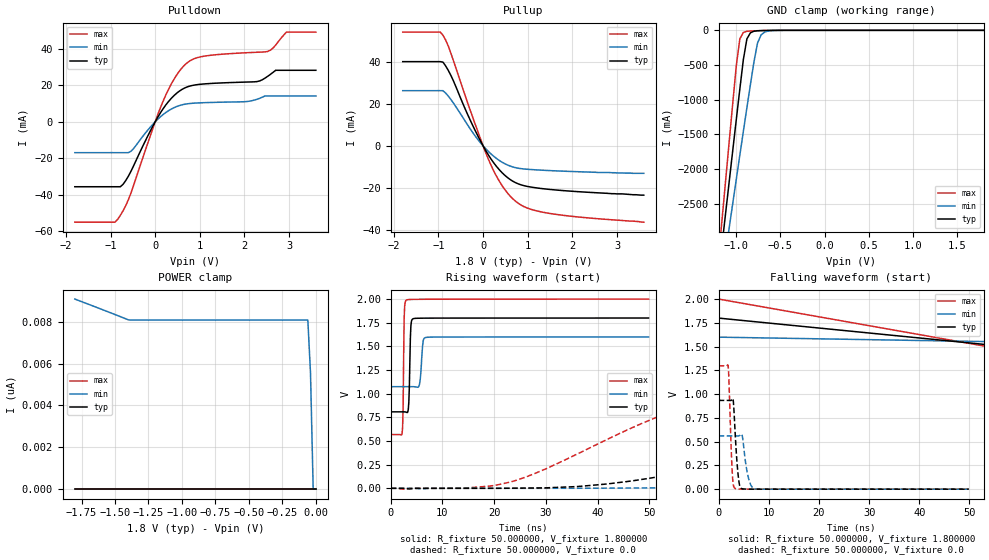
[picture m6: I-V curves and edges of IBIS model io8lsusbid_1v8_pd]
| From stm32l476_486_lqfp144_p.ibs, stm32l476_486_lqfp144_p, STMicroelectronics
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|   Model io8lsusbid_1v8_pd
[Model]  io8lsusbid_1v8_pd
Model_type I/O
Polarity   Non-Inverting
Enable   Active-Low
Vinl =   0.540000V
Vinh =   1.260000V
Vmeas =  0.900000V
Cref =   100.000000nF
Rref =   1.000000k
Vref =   1.800000V
C_comp   2.022300pF   2.021100pF   2.049600pF
[Temperature Range]   25.000000   0.125000k   -40.000000
[Pullup Reference]   1.800000V   1.600000V   2.000000V
[Pulldown Reference]   0.0V   0.0V   0.0V
[POWER Clamp Reference]   1.800000V   1.600000V   2.000000V
[GND Clamp Reference]   0.0V   0.0V   0.0V
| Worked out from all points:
|   slope of the pulldown table from 0 to 0.27 V, typ, clamps not added: 26.4 ohm
|   slope of the pullup table from 0 to 0.27 V, typ, clamps not added: 30.1 ohm
|   GND clamp passes 1 mA (typ) near -0.60 V on its own axis
|   rising waveform, R_fixture 50.000000, V_fixture 1.800000: 20-80 % time 250ps typ, 397ps min, 180ps max; typ from 0.808 V to 1.8 V
|   rising waveform, R_fixture 50.000000, V_fixture 0.0: 20-80 % time 65.2ns typ, 114ns min, 35.5ns max; typ from 0 V to 0.933 V
|   falling waveform, R_fixture 50.000000, V_fixture 1.800000: 20-80 % time 119ns typ, 161ns min, 92ns max; typ from 1.8 V to 0.808 V
|   falling waveform, R_fixture 50.000000, V_fixture 0.0: 20-80 % time 677ps typ, 985ps min, 516ps max; typ from 0.933 V to 0 V
[Pulldown]
|Voltage   I(typ)   I(min)   I(max)
-1.8V     -35.64mA   -16.93mA   -55.1mA
-840mV    -35.64mA   -16.93mA   -53.52mA
-720mV    -34.31mA   -16.93mA   -48.86mA
-540mV    -27.04mA   -16.13mA   -38.89mA
240mV     9.303mA    5.14mA     14.78mA
480mV     15.67mA    8.374mA    25.64mA
720mV     19.18mA    9.883mA    32.46mA
1.14V     20.87mA    10.54mA    36.19mA
2.28V     22.08mA    12.36mA    38.18mA
2.52V     24.96mA    14.18mA    38.63mA
2.94V     28.28mA    14.18mA    49.25mA
3.6V      28.28mA    14.18mA    49.25mA
[Pullup]
|Voltage   I(typ)   I(min)   I(max)
-1.8V     40.17mA    26.34mA    54.27mA
-960mV    40.17mA    26.34mA    54.27mA
-900mV    39.95mA    26.34mA    52.79mA
-780mV    36.01mA    23.74mA    47.65mA
-240mV    10.08mA    6.588mA    14.1mA
120mV     -4.38mA    -2.702mA   -6.45mA
240mV     -8.143mA   -5.004mA   -12mA
420mV     -12.68mA   -7.723mA   -18.77mA
720mV     -17.48mA   -10.37mA   -26.28mA
1.02V     -19.45mA   -11.2mA    -29.89mA
1.5V      -20.78mA   -11.79mA   -32.25mA
3.6V      -23.5mA    -13.1mA    -36.4mA
[GND_clamp]
|Voltage   I(typ)   I(min)   I(max)
-1.8V     -9.895A    -9.296A    -9.457A
-1.2V     -3.533A    -3.902A    -3.274A
-1.16V    -3.082A    -3.55A     -2.716A
-1.12V    -2.631A    -3.198A    -2.159A
-1.08V    -2.182A    -2.848A    -1.604A
-1V       -1.289A    -2.15A     -512mA
-960mV    -849.4mA   -1.803A    -123.8mA
-920mV    -422.4mA   -1.459A    -30.8mA
-880mV    -123.7mA   -1.118A    -13.64mA
-760mV    -6.331mA   -185.1mA   -5.703mA
-680mV    -2.582mA   -25.44mA   -2.917mA
1.8V      47.51uA    51.77uA    39.14uA
[POWER_clamp]
|Voltage   I(typ)   I(min)   I(max)
-1.8V     0A         9.088nA    0A
-1.4V     0A         8.095nA    0A
-60mV     0A         8.084nA    0A
-40mV     0A         5.54nA     0A
-20mV     0A         0A         0A
0V        0A         0A         0A
[Ramp]
| variable   typ   min   max
dV/dt_r  0.56008/65.14355n   0.33658/0.11418u   0.77826/35.46396n
dV/dt_f  0.59478/66.76513n   0.31500/0.11624u   0.85884/34.98706n
R_load = 50.000000
[Rising Waveform]
R_fixture= 50.000000
V_fixture= 1.800000
V_fixture_min= 1.600000
V_fixture_max= 2.000000
|time   V(typ)   V(min)   V(max)
0s        807.9mV    1.074V     568mV
2.202ns   808mV      1.074V     578.5mV
2.402ns   808mV      1.074V     854.5mV
2.603ns   807.9mV    1.074V     1.796V
3.003ns   804.1mV    1.074V     1.988V
3.504ns   909.1mV    1.074V     1.994V
3.904ns   1.718V     1.074V     1.995V
4.404ns   1.793V     1.074V     1.996V
6.807ns   1.798V     1.594V     1.997V
49.85ns   1.799V     1.599V     1.999V
[Rising Waveform]
R_fixture= 50.000000
V_fixture= 0.0
V_fixture_min= 0.0
V_fixture_max= 0.0
|time   V(typ)   V(min)   V(max)
0s        2.451nV    61.35nV    1.823nV
14.41ns   -57.33uV   -36.45uV   2.605mV
22.82ns   947.5uV    -21.17uV   62.61mV
42.04ns   47.24mV    1.669mV    522.1mV
64.86ns   258mV      15.76mV    999.5mV
81.68ns   438.4mV    43.77mV    1.173V
102.1ns   619.7mV    105.1mV    1.25V
156.2ns   858mV      294.9mV    1.292V
254.7ns   928.1mV    496.2mV    1.297V
598.2ns   933.5mV    560.6mV    1.297V
[Falling Waveform]
R_fixture= 50.000000
V_fixture= 1.800000
V_fixture_min= 1.600000
V_fixture_max= 2.000000
|time   V(typ)   V(min)   V(max)
0s        1.799V     1.599V     1.999V
150.2ns   1.015V     1.467V     597.7mV
300.3ns   820.3mV    1.137V     568.7mV
450.5ns   809.1mV    1.086V     568mV
750.8ns   807.9mV    1.075V     568mV
14.86us   807.9mV    1.074V     568mV
[Falling Waveform]
R_fixture= 50.000000
V_fixture= 0.0
V_fixture_min= 0.0
V_fixture_max= 0.0
|time   V(typ)   V(min)   V(max)
0s        933.5mV    560.6mV    1.297V
1.902ns   933.5mV    560.6mV    1.303V
2.703ns   945mV      560.6mV    191.4mV
2.903ns   941.8mV    560.6mV    53.39mV
3.303ns   585.2mV    560.5mV    7.214mV
4.004ns   97.7mV     560.3mV    1.122mV
4.705ns   4.645mV    564mV      346.3uV
5.806ns   337.8uV    150.6mV    148.9uV
7.107ns   -54.63uV   3.62mV     107.1uV
49.85ns   2.451nV    61.35nV    1.823nV
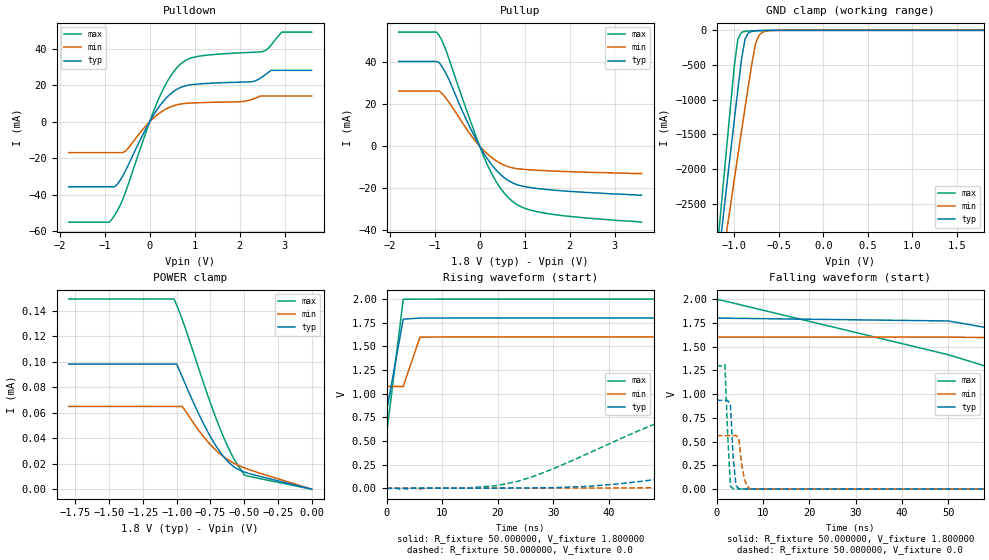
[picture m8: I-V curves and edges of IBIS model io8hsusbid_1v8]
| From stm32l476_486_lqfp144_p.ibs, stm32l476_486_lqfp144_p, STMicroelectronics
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|   Model io8hsusbid_1v8
[Model]  io8hsusbid_1v8
Model_type I/O
Polarity   Non-Inverting
Enable   Active-Low
Vinl =   0.540000V
Vinh =   1.260000V
Vmeas =  0.900000V
Cref =   100.000000nF
Rref =   1.000000k
Vref =   1.800000V
C_comp   2.022300pF   2.021100pF   2.049600pF
[Temperature Range]   25.000000   0.125000k   -40.000000
[Pullup Reference]   1.800000V   1.600000V   2.000000V
[Pulldown Reference]   0.0V   0.0V   0.0V
[POWER Clamp Reference]   1.800000V   1.600000V   2.000000V
[GND Clamp Reference]   0.0V   0.0V   0.0V
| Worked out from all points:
|   slope of the pulldown table from 0 to 0.27 V, typ, clamps not added: 26.4 ohm
|   slope of the pullup table from 0 to 0.27 V, typ, clamps not added: 30.1 ohm
|   GND clamp passes 1 mA (typ) near -0.60 V on its own axis
|   rising waveform, R_fixture 50.000000, V_fixture 1.800000: 20-80 % time 1.82ns typ, 1.81ns min, 1.81ns max; typ from 0.81 V to 1.8 V
|   rising waveform, R_fixture 50.000000, V_fixture 0.0: 20-80 % time 65ns typ, 101ns min, 35.5ns max; typ from 0.001 V to 0.935 V
|   falling waveform, R_fixture 50.000000, V_fixture 1.800000: 20-80 % time 76ns typ, 121ns min, 62.9ns max; typ from 1.8 V to 0.81 V
|   falling waveform, R_fixture 50.000000, V_fixture 0.0: 20-80 % time 747ps typ, 989ps min, 727ps max; typ from 0.935 V to 0.001 V
[Pulldown]
|Voltage   I(typ)   I(min)   I(max)
-1.8V     -35.64mA   -16.93mA   -55.1mA
-840mV    -35.64mA   -16.93mA   -53.52mA
-720mV    -34.31mA   -16.93mA   -48.86mA
-540mV    -27.04mA   -16.13mA   -38.89mA
240mV     9.303mA    5.14mA     14.78mA
480mV     15.67mA    8.374mA    25.64mA
720mV     19.18mA    9.883mA    32.46mA
1.14V     20.87mA    10.54mA    36.19mA
2.28V     22.08mA    12.36mA    38.18mA
2.52V     24.96mA    14.18mA    38.63mA
2.94V     28.3mA     14.18mA    49.27mA
3.6V      28.3mA     14.18mA    49.27mA
[Pullup]
|Voltage   I(typ)   I(min)   I(max)
-1.8V     40.48mA    26.32mA    54.53mA
-960mV    40.48mA    26.32mA    54.53mA
-900mV    39.98mA    26.32mA    52.91mA
-780mV    36mA       23.73mA    47.67mA
-240mV    10.08mA    6.588mA    14.1mA
120mV     -4.38mA    -2.702mA   -6.45mA
240mV     -8.143mA   -5.004mA   -12mA
420mV     -12.68mA   -7.723mA   -18.77mA
720mV     -17.48mA   -10.36mA   -26.28mA
1.02V     -19.45mA   -11.2mA    -29.88mA
1.5V      -20.78mA   -11.79mA   -32.25mA
3.6V      -23.5mA    -13.1mA    -36.4mA
[GND_clamp]
|Voltage   I(typ)   I(min)   I(max)
-1.8V     -9.895A    -9.296A    -9.457A
-1.2V     -3.533A    -3.902A    -3.274A
-1.16V    -3.082A    -3.55A     -2.716A
-1.12V    -2.631A    -3.198A    -2.159A
-1.08V    -2.182A    -2.848A    -1.604A
-1V       -1.289A    -2.15A     -512mA
-960mV    -849.4mA   -1.803A    -123.8mA
-920mV    -422.4mA   -1.459A    -30.79mA
-880mV    -123.7mA   -1.118A    -13.63mA
-760mV    -6.32mA    -185mA     -5.692mA
-680mV    -2.569mA   -25.43mA   -2.907mA
1.8V      0A         0A         0A
[POWER_clamp]
|Voltage   I(typ)   I(min)   I(max)
-1.8V     98.28uA    64.99uA    149.4uA
-1.02V    98.28uA    64.99uA    149.4uA
-1V       98.28uA    64.99uA    144.6uA
-960mV    88.57uA    64.99uA    133.7uA
-820mV    55.53uA    43.9uA     89.47uA
-760mV    43.23uA    36.15uA    70.81uA
-700mV    32.6uA     29.7uA     53.4uA
-640mV    24.05uA    24.57uA    37.82uA
-600mV    19.7uA     21.84uA    28.76uA
-560mV    16.51uA    19.57uA    21uA
-500mV    13.54uA    16.82uA    11.13uA
0V        0A         0A         0A
[Ramp]
| variable   typ   min   max
dV/dt_r  0.56071/65.15866n   0.33710/0.11418u   0.77863/35.46512n
dV/dt_f  0.59414/66.69548n   0.31416/0.11610u   0.85869/35.03890n
R_load = 50.000000
[Rising Waveform]
R_fixture= 50.000000
V_fixture= 1.800000
V_fixture_min= 1.600000
V_fixture_max= 2.000000
|time   V(typ)   V(min)   V(max)
0s        809.8mV    1.076V     568.8mV
3.003ns   1.788V     1.076V     1.997V
6.006ns   1.799V     1.597V     1.999V
297.3ns   1.8V       1.6V       2V
[Rising Waveform]
R_fixture= 50.000000
V_fixture= 0.0
V_fixture_min= 0.0
V_fixture_max= 0.0
|time   V(typ)   V(min)   V(max)
0s        726.2uV    1.152mV    482.7uV
23.42ns   3.609mV    2.691mV    71.9mV
41.44ns   46.16mV    4.275mV    507.9mV
60.06ns   208.7mV    13.96mV    923.5mV
72.67ns   345.5mV    30.62mV    1.099V
87.69ns   499.8mV    65.59mV    1.207V
121.3ns   741mV      187.8mV    1.278V
159.2ns   867.8mV    326.7mV    1.294V
218ns     923.7mV    479.9mV    1.298V
299.1ns   935.3mV    563.1mV    1.298V
[Falling Waveform]
R_fixture= 50.000000
V_fixture= 1.800000
V_fixture_min= 1.600000
V_fixture_max= 2.000000
|time   V(typ)   V(min)   V(max)
0s        1.8V       1.6V       2V
50.05ns   1.77V      1.6V       1.414V
100.1ns   1.343V     1.568V     664.5mV
150.2ns   975.3mV    1.437V     591.2mV
200.2ns   869.9mV    1.277V     575.4mV
250.2ns   835.5mV    1.179V     570.6mV
300.3ns   820.6mV    1.133V     569.5mV
400.4ns   812.2mV    1.096V     568.9mV
500.5ns   810.3mV    1.083V     568.8mV
4.955us   809.8mV    1.076V     568.8mV
[Falling Waveform]
R_fixture= 50.000000
V_fixture= 0.0
V_fixture_min= 0.0
V_fixture_max= 0.0
|time   V(typ)   V(min)   V(max)
0s        935.3mV    563.1mV    1.298V
1.802ns   935.3mV    563.1mV    1.31V
2.402ns   934.5mV    563.1mV    581.1mV
3.003ns   881.3mV    563.1mV    30.52mV
3.604ns   328.2mV    562.6mV    5.136mV
4.204ns   37.75mV    566.2mV    3.027mV
4.805ns   6.088mV    535.2mV    2.602mV
6.006ns   2.59mV     108.2mV    2.427mV
7.808ns   2.344mV    3.793mV    2.373mV
299.1ns   726.2uV    1.152mV    482.7uV
